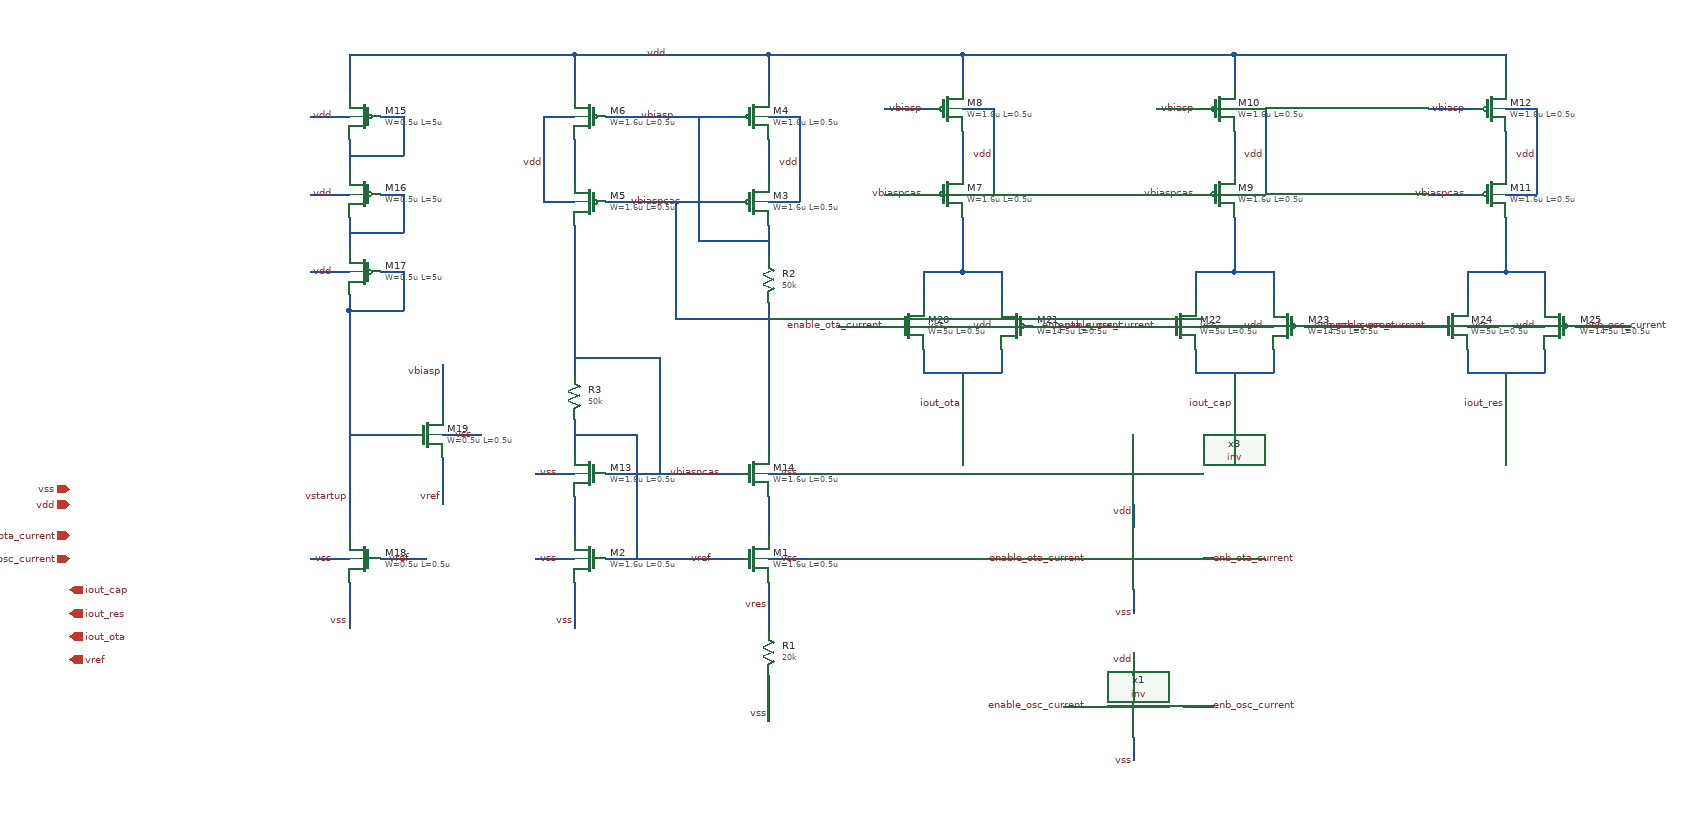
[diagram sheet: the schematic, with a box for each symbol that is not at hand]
v {xschem version=3.4.7 file_version=1.2}
G {}
K {}
V {}
S {}
E {}
N 500 -270 670 -270 {lab=vref}
N 710 -540 710 -460 {lab=vbiaspcas}
N 420 -270 460 -270 {lab=vss}
N 710 -270 760 -270 {lab=vss}
N 410 -270 420 -270 {lab=vss}
N 460 -240 460 -180 {lab=vss}
N 710 -240 710 -180 {lab=vres}
N 710 -600 710 -540 {lab=vbiaspcas}
N 460 -700 460 -540 {lab=vbiasncas}
N 710 -700 710 -660 {lab=vbiasp}
N 710 -810 710 -760 {lab=#net1}
N 710 -840 750 -840 {lab=vdd}
N 750 -840 750 -730 {lab=vdd}
N 710 -730 750 -730 {lab=vdd}
N 710 -920 710 -870 {lab=vdd}
N 460 -920 710 -920 {lab=vdd}
N 460 -810 460 -760 {lab=#net2}
N 420 -840 460 -840 {lab=vdd}
N 420 -840 420 -730 {lab=vdd}
N 420 -730 460 -730 {lab=vdd}
N 460 -920 460 -870 {lab=vdd}
N 500 -840 670 -840 {lab=vbiasp}
N 500 -730 670 -730 {lab=vbiaspcas}
N 620 -840 620 -680 {lab=vbiasp}
N 620 -680 710 -680 {lab=vbiasp}
N 590 -730 590 -580 {lab=vbiaspcas}
N 590 -580 710 -580 {lab=vbiaspcas}
N 710 -920 930 -920 {lab=vdd}
N 960 -820 960 -770 {lab=#net3}
N 960 -850 1000 -850 {lab=vdd}
N 1000 -850 1000 -740 {lab=vdd}
N 960 -740 1000 -740 {lab=vdd}
N 930 -920 960 -920 {lab=vdd}
N 960 -920 960 -880 {lab=vdd}
N 860 -850 920 -850 {lab=vbiasp}
N 860 -740 920 -740 {lab=vbiaspcas}
N 960 -710 960 -640 {lab=#net4}
N 1310 -820 1310 -770 {lab=#net5}
N 1310 -850 1350 -850 {lab=vdd}
N 1350 -850 1350 -740 {lab=vdd}
N 1310 -740 1350 -740 {lab=vdd}
N 1280 -920 1310 -920 {lab=vdd}
N 1310 -920 1310 -880 {lab=vdd}
N 1210 -850 1270 -850 {lab=vbiasp}
N 1210 -740 1270 -740 {lab=vbiaspcas}
N 1310 -710 1310 -640 {lab=#net6}
N 1660 -820 1660 -770 {lab=#net7}
N 1660 -850 1700 -850 {lab=vdd}
N 1700 -850 1700 -740 {lab=vdd}
N 1660 -740 1700 -740 {lab=vdd}
N 1630 -920 1660 -920 {lab=vdd}
N 1660 -920 1660 -880 {lab=vdd}
N 1560 -850 1620 -850 {lab=vbiasp}
N 1560 -740 1620 -740 {lab=vbiaspcas}
N 1660 -710 1660 -640 {lab=#net8}
N 960 -920 1160 -920 {lab=vdd}
N 1310 -920 1330 -920 {lab=vdd}
N 1330 -920 1480 -920 {lab=vdd}
N 710 -120 710 -60 {lab=vss}
N 420 -380 460 -380 {lab=vss}
N 410 -380 420 -380 {lab=vss}
N 460 -350 460 -300 {lab=#net9}
N 710 -460 710 -410 {lab=vbiaspcas}
N 710 -350 710 -300 {lab=#net10}
N 500 -380 670 -380 {lab=vbiasncas}
N 460 -450 460 -420 {lab=vref}
N 460 -420 460 -410 {lab=vref}
N 460 -540 460 -510 {lab=vbiasncas}
N 540 -430 540 -270 {lab=vref}
N 460 -430 540 -430 {lab=vref}
N 460 -530 570 -530 {lab=vbiasncas}
N 570 -530 570 -380 {lab=vbiasncas}
N 710 -380 760 -380 {lab=vss}
N 170 -920 460 -920 {lab=vdd}
N 170 -920 170 -870 {lab=vdd}
N 120 -840 170 -840 {lab=vdd}
N 210 -840 240 -840 {lab=#net11}
N 120 -740 170 -740 {lab=vdd}
N 210 -740 240 -740 {lab=#net12}
N 170 -810 170 -770 {lab=#net11}
N 120 -640 170 -640 {lab=vdd}
N 210 -640 240 -640 {lab=vstartup}
N 170 -710 170 -670 {lab=#net12}
N 130 -270 170 -270 {lab=vss}
N 120 -270 130 -270 {lab=vss}
N 170 -240 170 -180 {lab=vss}
N 210 -270 270 -270 {lab=vref}
N 290 -430 340 -430 {lab=vss}
N 170 -430 250 -430 {lab=vstartup}
N 290 -400 290 -350 {lab=vref}
N 290 -520 290 -460 {lab=vbiasp}
N 290 -350 290 -340 {lab=vref}
N 240 -840 240 -790 {lab=#net11}
N 170 -790 240 -790 {lab=#net11}
N 240 -740 240 -690 {lab=#net12}
N 170 -690 240 -690 {lab=#net12}
N 240 -640 240 -590 {lab=vstartup}
N 170 -590 240 -590 {lab=vstartup}
N 170 -610 170 -590 {lab=vstartup}
N 170 -590 170 -300 {lab=vstartup}
N 910 -640 910 -600 {lab=#net4}
N 910 -640 960 -640 {lab=#net4}
N 960 -640 1010 -640 {lab=#net4}
N 1010 -640 1010 -600 {lab=#net4}
N 910 -570 930 -570 {lab=vss}
N 930 -570 950 -570 {lab=vss}
N 970 -570 1010 -570 {lab=vdd33}
N 910 -540 910 -510 {lab=iout_ota}
N 910 -510 1010 -510 {lab=iout_ota}
N 1010 -540 1010 -510 {lab=iout_ota}
N 960 -510 960 -460 {lab=iout_ota}
N 800 -570 870 -570 {lab=enable_ota_current}
N 1050 -570 1110 -570 {lab=enb_ota_current}
N 1160 -920 1280 -920 {lab=vdd}
N 1260 -640 1260 -600 {lab=#net6}
N 1260 -640 1310 -640 {lab=#net6}
N 1310 -640 1360 -640 {lab=#net6}
N 1360 -640 1360 -600 {lab=#net6}
N 1260 -570 1280 -570 {lab=vss}
N 1280 -570 1300 -570 {lab=vss}
N 1320 -570 1360 -570 {lab=vdd33}
N 1260 -540 1260 -510 {lab=iout_cap}
N 1260 -510 1360 -510 {lab=iout_cap}
N 1360 -540 1360 -510 {lab=iout_cap}
N 1310 -510 1310 -460 {lab=iout_cap}
N 1150 -570 1220 -570 {lab=enable_osc_current}
N 1400 -570 1460 -570 {lab=enb_osc_current}
N 1480 -920 1630 -920 {lab=vdd}
N 1610 -640 1610 -600 {lab=#net8}
N 1610 -640 1660 -640 {lab=#net8}
N 1660 -640 1710 -640 {lab=#net8}
N 1710 -640 1710 -600 {lab=#net8}
N 1610 -570 1630 -570 {lab=vss}
N 1630 -570 1650 -570 {lab=vss}
N 1670 -570 1710 -570 {lab=vdd33}
N 1610 -540 1610 -510 {lab=iout_res}
N 1610 -510 1710 -510 {lab=iout_res}
N 1710 -540 1710 -510 {lab=iout_res}
N 1660 -510 1660 -460 {lab=iout_res}
N 1500 -570 1570 -570 {lab=enable_osc_current}
N 1750 -570 1810 -570 {lab=enb_osc_current}
N 1110 -570 1120 -570 {lab=enb_ota_current}
N 1460 -570 1470 -570 {lab=enb_osc_current}
N 1810 -570 1820 -570 {lab=enb_osc_current}
N 1180 -230 1180 -200 {lab=vss}
N 1180 -340 1180 -310 {lab=vdd}
N 1244 -270 1283 -270 {lab=enb_ota_current}
N 1090 -270 1130 -270 {lab=enable_ota_current}
N 1180 -40 1180 -10 {lab=vss}
N 1180 -150 1180 -120 {lab=vdd}
N 1244 -80 1283 -80 {lab=enb_osc_current}
N 1090 -80 1130 -80 {lab=enable_osc_current}
C {ipin.sym} -190 -300 0 0 {name=p1 lab=enable_ota_current}
C {ipin.sym} -190 -270 0 0 {name=p3 lab=enable_osc_current
}
C {iopin.sym} -190 -340 0 0 {name=p2 lab=vdd}
C {iopin.sym} -190 -360 0 0 {name=p4 lab=vss}
C {opin.sym} -190 -230 0 0 {name=p5 lab=iout_cap
}
C {opin.sym} -190 -170 0 0 {name=p6 lab=iout_ota
}
C {opin.sym} -190 -140 0 0 {name=p7 lab=vref
}
C {opin.sym} -190 -200 0 0 {name=p8 lab=iout_res
}
C {symbols/nfet_03v3.sym} 690 -270 0 0 {name=M1
L=0.5u
W=1.6u
nf=1
m=8
ad="'int((nf+1)/2) * W/nf * 0.18u'"
pd="'2*int((nf+1)/2) * (W/nf + 0.18u)'"
as="'int((nf+2)/2) * W/nf * 0.18u'"
ps="'2*int((nf+2)/2) * (W/nf + 0.18u)'"
nrd="'0.18u / W'" nrs="'0.18u / W'"
sa=0 sb=0 sd=0
model=nfet_03v3
spiceprefix=X
}
C {symbols/nfet_03v3.sym} 480 -270 0 1 {name=M2
L=0.5u
W=1.6u
nf=1
m=1
ad="'int((nf+1)/2) * W/nf * 0.18u'"
pd="'2*int((nf+1)/2) * (W/nf + 0.18u)'"
as="'int((nf+2)/2) * W/nf * 0.18u'"
ps="'2*int((nf+2)/2) * (W/nf + 0.18u)'"
nrd="'0.18u / W'" nrs="'0.18u / W'"
sa=0 sb=0 sd=0
model=nfet_03v3
spiceprefix=X
}
C {lab_wire.sym} 440 -270 0 0 {name=p10 sig_type=std_logic lab=vss}
C {lab_wire.sym} 750 -270 0 0 {name=p11 sig_type=std_logic lab=vss}
C {res.sym} 710 -630 0 0 {name=R2
value=50k
footprint=1206
device=resistor
m=1}
C {symbols/pfet_03v3.sym} 690 -730 0 0 {name=M3
L=0.5u
W=1.6u
nf=1
m=4
ad="'int((nf+1)/2) * W/nf * 0.18u'"
pd="'2*int((nf+1)/2) * (W/nf + 0.18u)'"
as="'int((nf+2)/2) * W/nf * 0.18u'"
ps="'2*int((nf+2)/2) * (W/nf + 0.18u)'"
nrd="'0.18u / W'" nrs="'0.18u / W'"
sa=0 sb=0 sd=0
model=pfet_03v3
spiceprefix=X
}
C {symbols/pfet_03v3.sym} 690 -840 0 0 {name=M4
L=0.5u
W=1.6u
nf=1
m=4
ad="'int((nf+1)/2) * W/nf * 0.18u'"
pd="'2*int((nf+1)/2) * (W/nf + 0.18u)'"
as="'int((nf+2)/2) * W/nf * 0.18u'"
ps="'2*int((nf+2)/2) * (W/nf + 0.18u)'"
nrd="'0.18u / W'" nrs="'0.18u / W'"
sa=0 sb=0 sd=0
model=pfet_03v3
spiceprefix=X
}
C {symbols/pfet_03v3.sym} 480 -730 0 1 {name=M5
L=0.5u
W=1.6u
nf=1
m=4
ad="'int((nf+1)/2) * W/nf * 0.18u'"
pd="'2*int((nf+1)/2) * (W/nf + 0.18u)'"
as="'int((nf+2)/2) * W/nf * 0.18u'"
ps="'2*int((nf+2)/2) * (W/nf + 0.18u)'"
nrd="'0.18u / W'" nrs="'0.18u / W'"
sa=0 sb=0 sd=0
model=pfet_03v3
spiceprefix=X
}
C {symbols/pfet_03v3.sym} 480 -840 0 1 {name=M6
L=0.5u
W=1.6u
nf=1
m=4
ad="'int((nf+1)/2) * W/nf * 0.18u'"
pd="'2*int((nf+1)/2) * (W/nf + 0.18u)'"
as="'int((nf+2)/2) * W/nf * 0.18u'"
ps="'2*int((nf+2)/2) * (W/nf + 0.18u)'"
nrd="'0.18u / W'" nrs="'0.18u / W'"
sa=0 sb=0 sd=0
model=pfet_03v3
spiceprefix=X
}
C {lab_wire.sym} 580 -920 0 0 {name=p12 sig_type=std_logic lab=vdd}
C {lab_wire.sym} 590 -840 0 0 {name=p13 sig_type=std_logic lab=vbiasp}
C {lab_wire.sym} 600 -730 0 0 {name=p14 sig_type=std_logic lab=vbiaspcas
}
C {lab_wire.sym} 420 -780 0 0 {name=p15 sig_type=std_logic lab=vdd}
C {lab_wire.sym} 750 -780 0 0 {name=p16 sig_type=std_logic lab=vdd}
C {lab_wire.sym} 640 -270 0 0 {name=p18 sig_type=std_logic lab=vref}
C {symbols/pfet_03v3.sym} 940 -740 0 0 {name=M7
L=0.5u
W=1.6u
nf=1
m=4
ad="'int((nf+1)/2) * W/nf * 0.18u'"
pd="'2*int((nf+1)/2) * (W/nf + 0.18u)'"
as="'int((nf+2)/2) * W/nf * 0.18u'"
ps="'2*int((nf+2)/2) * (W/nf + 0.18u)'"
nrd="'0.18u / W'" nrs="'0.18u / W'"
sa=0 sb=0 sd=0
model=pfet_03v3
spiceprefix=X
}
C {symbols/pfet_03v3.sym} 940 -850 0 0 {name=M8
L=0.5u
W=1.6u
nf=1
m=4
ad="'int((nf+1)/2) * W/nf * 0.18u'"
pd="'2*int((nf+1)/2) * (W/nf + 0.18u)'"
as="'int((nf+2)/2) * W/nf * 0.18u'"
ps="'2*int((nf+2)/2) * (W/nf + 0.18u)'"
nrd="'0.18u / W'" nrs="'0.18u / W'"
sa=0 sb=0 sd=0
model=pfet_03v3
spiceprefix=X
}
C {lab_wire.sym} 1000 -790 0 0 {name=p21 sig_type=std_logic lab=vdd}
C {lab_wire.sym} 910 -850 0 0 {name=p19 sig_type=std_logic lab=vbiasp}
C {lab_wire.sym} 910 -740 0 0 {name=p20 sig_type=std_logic lab=vbiaspcas
}
C {symbols/pfet_03v3.sym} 1290 -740 0 0 {name=M9
L=0.5u
W=1.6u
nf=1
m=4
ad="'int((nf+1)/2) * W/nf * 0.18u'"
pd="'2*int((nf+1)/2) * (W/nf + 0.18u)'"
as="'int((nf+2)/2) * W/nf * 0.18u'"
ps="'2*int((nf+2)/2) * (W/nf + 0.18u)'"
nrd="'0.18u / W'" nrs="'0.18u / W'"
sa=0 sb=0 sd=0
model=pfet_03v3
spiceprefix=X
}
C {symbols/pfet_03v3.sym} 1290 -850 0 0 {name=M10
L=0.5u
W=1.6u
nf=1
m=4
ad="'int((nf+1)/2) * W/nf * 0.18u'"
pd="'2*int((nf+1)/2) * (W/nf + 0.18u)'"
as="'int((nf+2)/2) * W/nf * 0.18u'"
ps="'2*int((nf+2)/2) * (W/nf + 0.18u)'"
nrd="'0.18u / W'" nrs="'0.18u / W'"
sa=0 sb=0 sd=0
model=pfet_03v3
spiceprefix=X
}
C {lab_wire.sym} 1350 -790 0 0 {name=p23 sig_type=std_logic lab=vdd}
C {lab_wire.sym} 1260 -850 0 0 {name=p24 sig_type=std_logic lab=vbiasp}
C {lab_wire.sym} 1260 -740 0 0 {name=p25 sig_type=std_logic lab=vbiaspcas
}
C {symbols/pfet_03v3.sym} 1640 -740 0 0 {name=M11
L=0.5u
W=1.6u
nf=1
m=4
ad="'int((nf+1)/2) * W/nf * 0.18u'"
pd="'2*int((nf+1)/2) * (W/nf + 0.18u)'"
as="'int((nf+2)/2) * W/nf * 0.18u'"
ps="'2*int((nf+2)/2) * (W/nf + 0.18u)'"
nrd="'0.18u / W'" nrs="'0.18u / W'"
sa=0 sb=0 sd=0
model=pfet_03v3
spiceprefix=X
}
C {symbols/pfet_03v3.sym} 1640 -850 0 0 {name=M12
L=0.5u
W=1.6u
nf=1
m=4
ad="'int((nf+1)/2) * W/nf * 0.18u'"
pd="'2*int((nf+1)/2) * (W/nf + 0.18u)'"
as="'int((nf+2)/2) * W/nf * 0.18u'"
ps="'2*int((nf+2)/2) * (W/nf + 0.18u)'"
nrd="'0.18u / W'" nrs="'0.18u / W'"
sa=0 sb=0 sd=0
model=pfet_03v3
spiceprefix=X
}
C {lab_wire.sym} 1700 -790 0 0 {name=p27 sig_type=std_logic lab=vdd}
C {lab_wire.sym} 1610 -850 0 0 {name=p28 sig_type=std_logic lab=vbiasp}
C {lab_wire.sym} 1610 -740 0 0 {name=p29 sig_type=std_logic lab=vbiaspcas
}
C {lab_wire.sym} 460 -190 0 0 {name=p9 sig_type=std_logic lab=vss}
C {res.sym} 710 -150 0 0 {name=R1
value=20k
footprint=1206
device=resistor
m=1}
C {lab_wire.sym} 710 -70 0 0 {name=p17 sig_type=std_logic lab=vss}
C {symbols/nfet_03v3.sym} 480 -380 0 1 {name=M13
L=0.5u
W=1.6u
nf=1
m=1
ad="'int((nf+1)/2) * W/nf * 0.18u'"
pd="'2*int((nf+1)/2) * (W/nf + 0.18u)'"
as="'int((nf+2)/2) * W/nf * 0.18u'"
ps="'2*int((nf+2)/2) * (W/nf + 0.18u)'"
nrd="'0.18u / W'" nrs="'0.18u / W'"
sa=0 sb=0 sd=0
model=nfet_03v3
spiceprefix=X
}
C {lab_wire.sym} 440 -380 0 0 {name=p31 sig_type=std_logic lab=vss}
C {symbols/nfet_03v3.sym} 690 -380 0 0 {name=M14
L=0.5u
W=1.6u
nf=1
m=1
ad="'int((nf+1)/2) * W/nf * 0.18u'"
pd="'2*int((nf+1)/2) * (W/nf + 0.18u)'"
as="'int((nf+2)/2) * W/nf * 0.18u'"
ps="'2*int((nf+2)/2) * (W/nf + 0.18u)'"
nrd="'0.18u / W'" nrs="'0.18u / W'"
sa=0 sb=0 sd=0
model=nfet_03v3
spiceprefix=X
}
C {res.sym} 460 -480 0 0 {name=R3
value=50k
footprint=1206
device=resistor
m=1}
C {lab_wire.sym} 750 -380 0 0 {name=p32 sig_type=std_logic lab=vss}
C {lab_wire.sym} 710 -210 0 0 {name=p33 sig_type=std_logic lab=vres}
C {lab_wire.sym} 650 -380 0 0 {name=p34 sig_type=std_logic lab=vbiasncas}
C {symbols/pfet_03v3.sym} 190 -840 0 1 {name=M15
L=5u
W=0.5u
nf=1
m=1
ad="'int((nf+1)/2) * W/nf * 0.18u'"
pd="'2*int((nf+1)/2) * (W/nf + 0.18u)'"
as="'int((nf+2)/2) * W/nf * 0.18u'"
ps="'2*int((nf+2)/2) * (W/nf + 0.18u)'"
nrd="'0.18u / W'" nrs="'0.18u / W'"
sa=0 sb=0 sd=0
model=pfet_03v3
spiceprefix=X
}
C {lab_wire.sym} 150 -840 0 0 {name=p35 sig_type=std_logic lab=vdd}
C {symbols/pfet_03v3.sym} 190 -740 0 1 {name=M16
L=5u
W=0.5u
nf=1
m=1
ad="'int((nf+1)/2) * W/nf * 0.18u'"
pd="'2*int((nf+1)/2) * (W/nf + 0.18u)'"
as="'int((nf+2)/2) * W/nf * 0.18u'"
ps="'2*int((nf+2)/2) * (W/nf + 0.18u)'"
nrd="'0.18u / W'" nrs="'0.18u / W'"
sa=0 sb=0 sd=0
model=pfet_03v3
spiceprefix=X
}
C {lab_wire.sym} 150 -740 0 0 {name=p36 sig_type=std_logic lab=vdd}
C {symbols/pfet_03v3.sym} 190 -640 0 1 {name=M17
L=5u
W=0.5u
nf=1
m=1
ad="'int((nf+1)/2) * W/nf * 0.18u'"
pd="'2*int((nf+1)/2) * (W/nf + 0.18u)'"
as="'int((nf+2)/2) * W/nf * 0.18u'"
ps="'2*int((nf+2)/2) * (W/nf + 0.18u)'"
nrd="'0.18u / W'" nrs="'0.18u / W'"
sa=0 sb=0 sd=0
model=pfet_03v3
spiceprefix=X
}
C {lab_wire.sym} 150 -640 0 0 {name=p37 sig_type=std_logic lab=vdd}
C {symbols/nfet_03v3.sym} 190 -270 0 1 {name=M18
L=0.5u
W=0.5u
nf=1
m=1
ad="'int((nf+1)/2) * W/nf * 0.18u'"
pd="'2*int((nf+1)/2) * (W/nf + 0.18u)'"
as="'int((nf+2)/2) * W/nf * 0.18u'"
ps="'2*int((nf+2)/2) * (W/nf + 0.18u)'"
nrd="'0.18u / W'" nrs="'0.18u / W'"
sa=0 sb=0 sd=0
model=nfet_03v3
spiceprefix=X
}
C {lab_wire.sym} 150 -270 0 0 {name=p38 sig_type=std_logic lab=vss}
C {lab_wire.sym} 170 -190 0 0 {name=p39 sig_type=std_logic lab=vss}
C {lab_wire.sym} 250 -270 0 0 {name=p40 sig_type=std_logic lab=vref}
C {symbols/nfet_03v3.sym} 270 -430 0 0 {name=M19
L=0.5u
W=0.5u
nf=1
m=1
ad="'int((nf+1)/2) * W/nf * 0.18u'"
pd="'2*int((nf+1)/2) * (W/nf + 0.18u)'"
as="'int((nf+2)/2) * W/nf * 0.18u'"
ps="'2*int((nf+2)/2) * (W/nf + 0.18u)'"
nrd="'0.18u / W'" nrs="'0.18u / W'"
sa=0 sb=0 sd=0
model=nfet_03v3
spiceprefix=X
}
C {lab_wire.sym} 330 -430 0 0 {name=p41 sig_type=std_logic lab=vss}
C {lab_wire.sym} 290 -350 0 0 {name=p42 sig_type=std_logic lab=vref}
C {lab_wire.sym} 290 -510 0 0 {name=p43 sig_type=std_logic lab=vbiasp}
C {lab_wire.sym} 170 -350 0 0 {name=p44 sig_type=std_logic lab=vstartup}
C {symbols/nfet_03v3.sym} 890 -570 0 0 {name=M20
L=0.5u
W=5u
nf=1
m=1
ad="'int((nf+1)/2) * W/nf * 0.18u'"
pd="'2*int((nf+1)/2) * (W/nf + 0.18u)'"
as="'int((nf+2)/2) * W/nf * 0.18u'"
ps="'2*int((nf+2)/2) * (W/nf + 0.18u)'"
nrd="'0.18u / W'" nrs="'0.18u / W'"
sa=0 sb=0 sd=0
model=nfet_03v3
spiceprefix=X
}
C {symbols/pfet_03v3.sym} 1030 -570 0 1 {name=M21
L=0.5u
W=14.5u
nf=1
m=4
ad="'int((nf+1)/2) * W/nf * 0.18u'"
pd="'2*int((nf+1)/2) * (W/nf + 0.18u)'"
as="'int((nf+2)/2) * W/nf * 0.18u'"
ps="'2*int((nf+2)/2) * (W/nf + 0.18u)'"
nrd="'0.18u / W'" nrs="'0.18u / W'"
sa=0 sb=0 sd=0
model=pfet_03v3
spiceprefix=X
}
C {lab_wire.sym} 940 -570 0 0 {name=p22 sig_type=std_logic lab=vss}
C {lab_wire.sym} 1000 -570 0 0 {name=p26 sig_type=std_logic lab=vdd}
C {symbols/nfet_03v3.sym} 1240 -570 0 0 {name=M22
L=0.5u
W=5u
nf=1
m=1
ad="'int((nf+1)/2) * W/nf * 0.18u'"
pd="'2*int((nf+1)/2) * (W/nf + 0.18u)'"
as="'int((nf+2)/2) * W/nf * 0.18u'"
ps="'2*int((nf+2)/2) * (W/nf + 0.18u)'"
nrd="'0.18u / W'" nrs="'0.18u / W'"
sa=0 sb=0 sd=0
model=nfet_03v3
spiceprefix=X
}
C {symbols/pfet_03v3.sym} 1380 -570 0 1 {name=M23
L=0.5u
W=14.5u
nf=1
m=4
ad="'int((nf+1)/2) * W/nf * 0.18u'"
pd="'2*int((nf+1)/2) * (W/nf + 0.18u)'"
as="'int((nf+2)/2) * W/nf * 0.18u'"
ps="'2*int((nf+2)/2) * (W/nf + 0.18u)'"
nrd="'0.18u / W'" nrs="'0.18u / W'"
sa=0 sb=0 sd=0
model=pfet_03v3
spiceprefix=X
}
C {lab_wire.sym} 1290 -570 0 0 {name=p30 sig_type=std_logic lab=vss}
C {lab_wire.sym} 1350 -570 0 0 {name=p45 sig_type=std_logic lab=vdd}
C {symbols/nfet_03v3.sym} 1590 -570 0 0 {name=M24
L=0.5u
W=5u
nf=1
m=1
ad="'int((nf+1)/2) * W/nf * 0.18u'"
pd="'2*int((nf+1)/2) * (W/nf + 0.18u)'"
as="'int((nf+2)/2) * W/nf * 0.18u'"
ps="'2*int((nf+2)/2) * (W/nf + 0.18u)'"
nrd="'0.18u / W'" nrs="'0.18u / W'"
sa=0 sb=0 sd=0
model=nfet_03v3
spiceprefix=X
}
C {symbols/pfet_03v3.sym} 1730 -570 0 1 {name=M25
L=0.5u
W=14.5u
nf=1
m=4
ad="'int((nf+1)/2) * W/nf * 0.18u'"
pd="'2*int((nf+1)/2) * (W/nf + 0.18u)'"
as="'int((nf+2)/2) * W/nf * 0.18u'"
ps="'2*int((nf+2)/2) * (W/nf + 0.18u)'"
nrd="'0.18u / W'" nrs="'0.18u / W'"
sa=0 sb=0 sd=0
model=pfet_03v3
spiceprefix=X
}
C {lab_wire.sym} 1640 -570 0 0 {name=p46 sig_type=std_logic lab=vss}
C {lab_wire.sym} 1700 -570 0 0 {name=p47 sig_type=std_logic lab=vdd}
C {lab_wire.sym} 960 -470 0 0 {name=p48 sig_type=std_logic lab=iout_ota
}
C {lab_wire.sym} 1310 -470 0 0 {name=p49 sig_type=std_logic lab=iout_cap}
C {lab_wire.sym} 1660 -470 0 0 {name=p50 sig_type=std_logic lab=iout_res}
C {DACFUTURE_EDU/inv/inv.sym} 1280 -250 0 0 {name=x3}
C {lab_wire.sym} 1180 -330 0 0 {name=p51 sig_type=std_logic lab=vdd}
C {lab_wire.sym} 1280 -270 0 1 {name=p52 sig_type=std_logic lab=enb_ota_current
}
C {lab_wire.sym} 1180 -200 0 0 {name=p53 sig_type=std_logic lab=vss}
C {lab_wire.sym} 1120 -270 0 0 {name=p54 sig_type=std_logic lab=enable_ota_current

}
C {DACFUTURE_EDU/inv/inv.sym} 1280 -60 0 0 {name=x1}
C {lab_wire.sym} 1180 -140 0 0 {name=p55 sig_type=std_logic lab=vdd}
C {lab_wire.sym} 1280 -80 0 1 {name=p56 sig_type=std_logic lab=enb_osc_current}
C {lab_wire.sym} 1180 -10 0 0 {name=p57 sig_type=std_logic lab=vss}
C {lab_wire.sym} 1120 -80 0 0 {name=p58 sig_type=std_logic lab=enable_osc_current
}
C {lab_wire.sym} 860 -570 0 0 {name=p59 sig_type=std_logic lab=enable_ota_current

}
C {lab_wire.sym} 1060 -570 0 1 {name=p60 sig_type=std_logic lab=enb_ota_current
}
C {lab_wire.sym} 1210 -570 2 1 {name=p61 sig_type=std_logic lab=enable_osc_current
}
C {lab_wire.sym} 1410 -570 2 0 {name=p62 sig_type=std_logic lab=enb_osc_current}
C {lab_wire.sym} 1560 -570 0 0 {name=p63 sig_type=std_logic lab=enable_osc_current
}
C {lab_wire.sym} 1760 -570 0 1 {name=p64 sig_type=std_logic lab=enb_osc_current}
